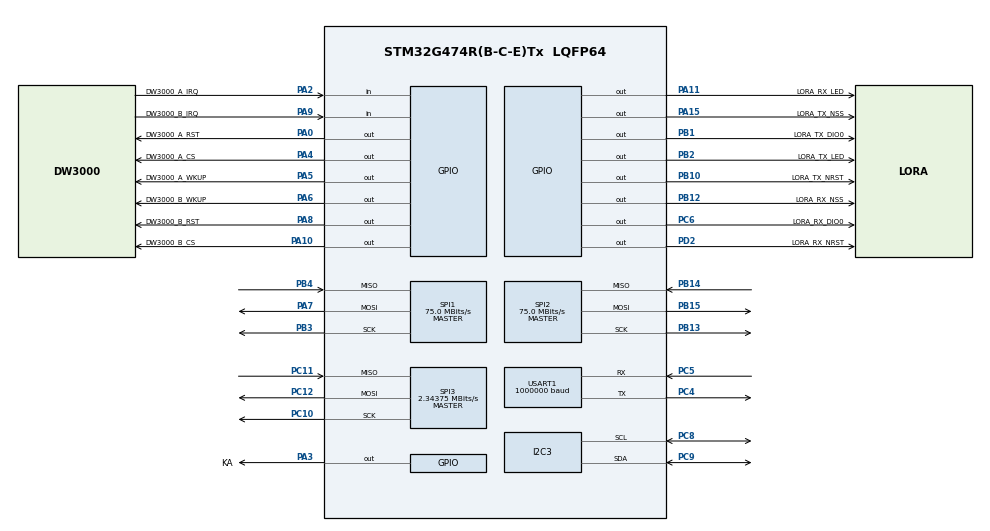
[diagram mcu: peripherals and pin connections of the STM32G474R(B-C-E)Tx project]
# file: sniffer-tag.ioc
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Mcu.Family=STM32G4
Mcu.Name=STM32G474R(B-C-E)Tx
Mcu.Package=LQFP64
NVIC.PriorityGroup=NVIC_PRIORITYGROUP_4
PA0.GPIO_Label=DW3000_A_RST
PA0.Signal=GPIO_Output
PA10.GPIO_Label=DW3000_B_CS
PA10.Signal=GPIO_Output
PA11.GPIO_Label=LORA_RX_LED
PA11.Signal=GPIO_Output
PA13.Signal=SYS_JTMS-SWDIO
PA14.Signal=SYS_JTCK-SWCLK
PA15.GPIO_Label=LORA_TX_NSS
PA15.Signal=GPIO_Output
PA2.GPIO_Label=DW3000_A_IRQ
PA2.Signal=GPIO_Input
PA3.GPIO_Label=KA
PA3.Signal=GPIO_Output
PA4.GPIO_Label=DW3000_A_CS
PA4.Signal=GPIO_Output
PA5.GPIO_Label=DW3000_A_WKUP
PA5.Signal=GPIO_Output
PA6.GPIO_Label=DW3000_B_WKUP
PA6.Signal=GPIO_Output
PA7.Mode=Full_Duplex_Master
PA7.Signal=SPI1_MOSI
PA8.GPIO_Label=DW3000_B_RST
PA8.Signal=GPIO_Output
PA9.GPIO_Label=DW3000_B_IRQ
PA9.Signal=GPIO_Input
PB1.GPIO_Label=LORA_TX_DIO0
PB1.Signal=GPIO_Output
PB10.GPIO_Label=LORA_TX_NRST
PB10.Signal=GPIO_Output
PB12.GPIO_Label=LORA_RX_NSS
PB12.Signal=GPIO_Output
PB13.Mode=Full_Duplex_Master
PB13.Signal=SPI2_SCK
PB14.Mode=Full_Duplex_Master
PB14.Signal=SPI2_MISO
PB15.Mode=Full_Duplex_Master
PB15.Signal=SPI2_MOSI
PB2.GPIO_Label=LORA_TX_LED
PB2.Signal=GPIO_Output
PB3.Mode=Full_Duplex_Master
PB3.Signal=SPI1_SCK
PB4.Mode=Full_Duplex_Master
PB4.Signal=SPI1_MISO
PC10.Mode=Full_Duplex_Master
PC10.Signal=SPI3_SCK
PC11.Mode=Full_Duplex_Master
PC11.Signal=SPI3_MISO
PC12.Mode=Full_Duplex_Master
PC12.Signal=SPI3_MOSI
PC4.Mode=Asynchronous
PC4.Signal=USART1_TX
PC5.Mode=Asynchronous
PC5.Signal=USART1_RX
PC6.GPIO_Label=LORA_RX_DIO0
PC6.Signal=GPIO_Output
PC8.Mode=I2C
PC8.Signal=I2C3_SCL
PC9.Mode=I2C
PC9.Signal=I2C3_SDA
PD2.GPIO_Label=LORA_RX_NRST
PD2.Signal=GPIO_Output
ProjectManager.HeapSize=0x200
ProjectManager.StackSize=0x400
ProjectManager.TargetToolchain=STM32CubeIDE
RCC.ADC12Freq_Value=150000000
RCC.ADC345Freq_Value=150000000
RCC.AHBFreq_Value=150000000
RCC.APB1Freq_Value=150000000
RCC.APB1TimFreq_Value=150000000
RCC.APB2Freq_Value=150000000
RCC.APB2TimFreq_Value=150000000
RCC.CortexFreq_Value=150000000
RCC.EXTERNAL_CLOCK_VALUE=12288000
RCC.HCLKFreq_Value=150000000
RCC.HSE_VALUE=8000000
RCC.HSI48_VALUE=48000000
RCC.HSI_VALUE=16000000
RCC.LSE_VALUE=32768
RCC.PLLM=RCC_PLLM_DIV4
RCC.PLLN=75
RCC.SYSCLKFreq_VALUE=150000000
RCC.SYSCLKSource=RCC_SYSCLKSOURCE_PLLCLK
RCC.USBFreq_Value=150000000
RCC.VCOOutputFreq_Value=300000000
SPI1.CalculateBaudRate=75.0 MBits/s
SPI1.Direction=SPI_DIRECTION_2LINES
SPI1.Mode=SPI_MODE_MASTER
SPI1.VirtualType=VM_MASTER
SPI2.CalculateBaudRate=75.0 MBits/s
SPI2.Direction=SPI_DIRECTION_2LINES
SPI2.Mode=SPI_MODE_MASTER
SPI2.VirtualType=VM_MASTER
SPI3.BaudRatePrescaler=SPI_BAUDRATEPRESCALER_64
SPI3.CalculateBaudRate=2.34375 MBits/s
SPI3.DataSize=SPI_DATASIZE_8BIT
SPI3.Direction=SPI_DIRECTION_2LINES
SPI3.Mode=SPI_MODE_MASTER
SPI3.NSSPMode=SPI_NSS_PULSE_DISABLE
SPI3.VirtualType=VM_MASTER
USART1.BaudRate=1000000
USART1.VirtualMode-Asynchronous=VM_ASYNC
VP_SYS_VS_DBSignals.Mode=DisableDeadBatterySignals
board=custom

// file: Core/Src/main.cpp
/* USER CODE BEGIN Header */
/**
 ******************************************************************************
 * @file           : main.c
 * @brief          : Main program body
 ******************************************************************************
 * @attention
 *
 * Copyright (c) 2024 STMicroelectronics.
 * All rights reserved.
 *
 * This software is licensed under terms that can be found in the LICENSE file
 * in the root directory of this software component.
 * If no LICENSE file comes with this software, it is provided AS-IS.
 *
 ******************************************************************************
 */
/* USER CODE END Header */
#include <sniffer_tag.hpp>
#include "SX1278.h"
#include "main.h"

I2C_HandleTypeDef hi2c3;

SPI_HandleTypeDef hspi1;
SPI_HandleTypeDef hspi2;
SPI_HandleTypeDef hspi3;

UART_HandleTypeDef huart1;

/* USER CODE BEGIN PV */
double *distance_ptr;
TAG_t *tag;
int size = 0;
uint8_t running_device = DEV_UWB3000F27;
Uwb_HW_t uwb_hw_a;
Uwb_HW_t uwb_hw_b;
Uwb_HW_t *hw;
dwt_local_data_t *pdw3000local;
uint8_t crcTable[256];
uint8_t recvChar;
LORA_t lora;
SX1276_HW_t sx1276_hw_tx;
SX1276_HW_t sx1276_hw_rx;
/* USER CODE END PV */

void SystemClock_Config(void);
static void MX_GPIO_Init(void);
static void MX_USART1_UART_Init(void);
static void MX_I2C3_Init(void);
static void MX_SPI1_Init(void);
static void MX_SPI2_Init(void);
static void MX_SPI3_Init(void);

int main(void) {

	/* MCU Configuration--------------------------------------------------------*/

	/* Reset of all peripherals, Initializes the Flash interface and the Systick. */
	HAL_Init();

	/* Configure the system clock */
	SystemClock_Config();

	/* Initialize all configured peripherals */
	MX_GPIO_Init();
	MX_USART1_UART_Init();
	MX_I2C3_Init();
	MX_SPI1_Init();
	MX_SPI2_Init();
	MX_SPI3_Init();
	/* USER CODE BEGIN 2 */
	pdw3000local = new dwt_local_data_t;

	init_sx1276_hw(&sx1276_hw_tx, &hspi1, LORA_TX_NSS_GPIO_Port,
	LORA_TX_NSS_Pin,
	LORA_TX_NRST_GPIO_Port, LORA_TX_NRST_Pin,
	LORA_TX_DIO0_GPIO_Port,
	LORA_TX_DIO0_Pin);

	init_sx1276_hw(&sx1276_hw_rx, &hspi2, LORA_RX_NSS_GPIO_Port,
	LORA_RX_NSS_Pin,
	LORA_RX_NRST_GPIO_Port, LORA_RX_NRST_Pin,
	LORA_RX_DIO0_GPIO_Port,
	LORA_RX_DIO0_Pin);

	HAL_GPIO_WritePin(LORA_TX_LED_GPIO_Port, LORA_TX_LED_Pin, GPIO_PIN_SET);
	HAL_GPIO_WritePin(LORA_RX_LED_GPIO_Port, LORA_RX_LED_Pin, GPIO_PIN_SET);

	lora_init(&lora, &sx1276_hw_tx, &sx1276_hw_rx);

	TAG_List list = { NULL, 0 };

	HAL_GPIO_WritePin(DW3000_B_WKUP_GPIO_Port, DW3000_B_WKUP_Pin, GPIO_PIN_RESET);
	HAL_GPIO_WritePin(DW3000_A_WKUP_GPIO_Port, DW3000_A_WKUP_Pin, GPIO_PIN_RESET);
	HAL_GPIO_WritePin(DW3000_A_CS_GPIO_Port, DW3000_A_CS_Pin, GPIO_PIN_RESET);
	HAL_GPIO_WritePin(DW3000_B_CS_GPIO_Port, DW3000_B_CS_Pin, GPIO_PIN_RESET);

	init_uwb_device(&uwb_hw_a, &hspi3, DW3000_A_CS_GPIO_Port,
	DW3000_A_CS_Pin,
	DW3000_A_RST_GPIO_Port, DW3000_A_RST_Pin);

	init_uwb_device(&uwb_hw_b, &hspi3, DW3000_B_CS_GPIO_Port, DW3000_B_CS_Pin,
			DW3000_B_RST_GPIO_Port, DW3000_B_RST_Pin);

	TAG_t tag;
	reset_TAG_values(&tag);

	TAG_STATUS_t tag_status = TAG_DISCOVERY;
	uint32_t lora_send_timeout = 5000;
	uint32_t lora_send_ticks = HAL_GetTick();
	uint32_t query_timeout = 1000;
	uint32_t query_ticks;

	RDSS_status_t rdss_status;

	/* USER CODE END 2 */

	/* Infinite loop */
	while (1) {
		if (tag_status == TAG_DISCOVERY) {

			if (hw == &uwb_hw_a) {
				hw = &uwb_hw_b;
				tag.distance = &(tag.distance_b);
			} else {
				hw = &uwb_hw_a;
				tag.distance = &(tag.distance_a);
			}

			tag_status = tag_discovery(&tag);

			if (tag_status != TAG_SEND_TIMESTAMP_QUERY)
				tag_status = TAG_DISCOVERY;
			else
				query_ticks = HAL_GetTick();
			set_battery_voltage(&(tag.battery_voltage));
			set_temperature(&(tag.temperature));
			debug(tag, tag_status);

		} else if (tag_status == TAG_SEND_TIMESTAMP_QUERY) {
			if (tag.readings < DISTANCE_READINGS) {
				if (hw == &uwb_hw_a) {
					hw = &uwb_hw_b;
					tag.distance = &(tag.distance_b);
				} else {
					hw = &uwb_hw_a;
					tag.distance = &(tag.distance_a);
				}
				tag.command = TAG_TIMESTAMP_QUERY;
			}
			if (tag.readings == DISTANCE_READINGS - 2) {
				tag.command = TAG_SET_SLEEP_MODE;
				tag_status = TAG_SEND_SET_SLEEP;
			}
			debug(tag, tag_status);
			tag_status = tag_send_timestamp_query(&tag);

			if (tag_status == TAG_SEND_TIMESTAMP_QUERY) {
				tag.readings++;
				tag_status = TAG_SEND_TIMESTAMP_QUERY;

			} else if (tag_status == TAG_END_READINGS) {
				double distance_a_sum = 0;
				double distance_b_sum = 0;
				for (uint8_t i = 0; i < tag.distance_a.counter; i++)
					distance_a_sum += tag.distance_a.readings[i];

				for (uint8_t i = 0; i < tag.distance_b.counter; i++)
					distance_b_sum += tag.distance_b.readings[i];

				tag.distance_a.value = (uint16_t) ((distance_a_sum * 100)
						/ tag.distance_a.counter);
				tag.distance_b.value = (uint16_t) ((distance_b_sum * 100)
						/ tag.distance_b.counter);
				insert_tag(&list, tag);
				tag_status = TAG_DISCOVERY;
				reset_TAG_values(&tag);
			} else {
				tag_status = TAG_SEND_TIMESTAMP_QUERY;
			}
			debug(tag, tag_status);
			if (HAL_GetTick() - query_ticks > query_timeout) {
				tag_status = TAG_DISCOVERY;
				reset_TAG_values(&tag);
			}

		}

		if (read_lora_packet(&lora) > 0) {
			rdss_status = rdss_validation(lora.rxData, lora.rxSize, 0x00);
			if (rdss_status == DATA_OK) {
				uint8_t *rx = lora.rxData;
				size_t temp_value = 1 + list.count * SERIALIZED_TAG_SIZE; // Or use uint32_t
				uint8_t tag_bytes = (uint8_t) temp_value;
				uint8_t response_length = calculate_frame_length(tag_bytes);
				uint8_t tx[response_length];
				memset(tx, 0, response_length);
				memcpy(tx, rx, LORA_DATA_LENGHT_INDEX_1);
				memcpy(tx + LORA_DATA_LENGHT_INDEX_1, &tag_bytes,
						sizeof(tag_bytes));
				uint8_t *tx_data = tx + LORA_DATA_START_INDEX;
				tx_data[0] = list.count;
				tx_data++;
				serialize_tag_list(&list, tx_data);
				uint8_t CRC_INDEX = LORA_DATA_START_INDEX
						+ tx[LORA_DATA_LENGHT_INDEX_1];
				uint8_t END_INDEX = CRC_INDEX + CRC_SIZE;
				setCrc(tx, CRC_INDEX);
				tx[END_INDEX] = LTEL_END_MARK;
				HAL_GPIO_WritePin(LORA_TX_LED_GPIO_Port, LORA_TX_LED_Pin,
						GPIO_PIN_RESET);
				write_lora_RegFifo(lora.txhw, tx, response_length);
				start_lora_transmission(lora.txhw);
				HAL_GPIO_WritePin(LORA_TX_LED_GPIO_Port, LORA_TX_LED_Pin,
						GPIO_PIN_SET);
				serialize_tag_list(&list, tx_data);
				free(tx);
				print_all_tags(&list, tag_status);
				print_serialized_tags(&list);
				free_tag_list(&list);
				restart_lora_rx_continuous_mode(&lora);
			} else {
				lora_reset(lora.txhw);
				lora_reset(lora.rxhw);
				init_lora_parameters(&lora);
			}
		}

		if (((HAL_GetTick() - lora_send_ticks) > lora_send_timeout)
				&& tag_status == TAG_DISCOVERY) {
			debug_status(tag_status);
			size_t temp_value = 1 + list.count * SERIALIZED_TAG_SIZE; // Or use uint32_t
			uint8_t tag_bytes = (uint8_t) temp_value;
			uint8_t response_length = calculate_frame_length(tag_bytes);
			uint8_t tx[response_length];
			memset(tx, 0, response_length);
			memcpy(tx + LORA_DATA_LENGHT_INDEX_1, &tag_bytes,
					sizeof(tag_bytes));
			uint8_t *tx_data = tx + LORA_DATA_START_INDEX;
			tx_data[0] = list.count;
			tx_data++;
			serialize_tag_list(&list, tx_data);
			uint8_t CRC_INDEX = LORA_DATA_START_INDEX
					+ tx[LORA_DATA_LENGHT_INDEX_1];
			uint8_t END_INDEX = CRC_INDEX + CRC_SIZE;
			setCrc(tx, CRC_INDEX);
			tx[END_INDEX] = LTEL_END_MARK;
			print_all_tags(&list, tag_status);
			print_serialized_tags(&list);
			print_tx_hex(tx, response_length);
			free_tag_list(&list);
			lora_send_ticks = HAL_GetTick();
		}

	}
}

void SystemClock_Config(void) {
	RCC_OscInitTypeDef RCC_OscInitStruct = { 0 };
	RCC_ClkInitTypeDef RCC_ClkInitStruct = { 0 };

	/** Configure the main internal regulator output voltage
	 */
	HAL_PWREx_ControlVoltageScaling(PWR_REGULATOR_VOLTAGE_SCALE1);

	/** Initializes the RCC Oscillators according to the specified parameters
	 * in the RCC_OscInitTypeDef structure.
	 */
	RCC_OscInitStruct.OscillatorType = RCC_OSCILLATORTYPE_HSI;
	RCC_OscInitStruct.HSIState = RCC_HSI_ON;
	RCC_OscInitStruct.HSICalibrationValue = RCC_HSICALIBRATION_DEFAULT;
	RCC_OscInitStruct.PLL.PLLState = RCC_PLL_NONE;
	if (HAL_RCC_OscConfig(&RCC_OscInitStruct) != HAL_OK) {
		Error_Handler();
	}

	/** Initializes the CPU, AHB and APB buses clocks
	 */
	RCC_ClkInitStruct.ClockType = RCC_CLOCKTYPE_HCLK | RCC_CLOCKTYPE_SYSCLK
			| RCC_CLOCKTYPE_PCLK1 | RCC_CLOCKTYPE_PCLK2;
	RCC_ClkInitStruct.SYSCLKSource = RCC_SYSCLKSOURCE_HSI;
	RCC_ClkInitStruct.AHBCLKDivider = RCC_SYSCLK_DIV1;
	RCC_ClkInitStruct.APB1CLKDivider = RCC_HCLK_DIV1;
	RCC_ClkInitStruct.APB2CLKDivider = RCC_HCLK_DIV1;

	if (HAL_RCC_ClockConfig(&RCC_ClkInitStruct, FLASH_LATENCY_0) != HAL_OK) {
		Error_Handler();
	}
}

static void MX_I2C3_Init(void) {

	hi2c3.Instance = I2C3;
	hi2c3.Init.Timing = 0x00303D5B;
	hi2c3.Init.OwnAddress1 = 0;
	hi2c3.Init.AddressingMode = I2C_ADDRESSINGMODE_7BIT;
	hi2c3.Init.DualAddressMode = I2C_DUALADDRESS_DISABLE;
	hi2c3.Init.OwnAddress2 = 0;
	hi2c3.Init.OwnAddress2Masks = I2C_OA2_NOMASK;
	hi2c3.Init.GeneralCallMode = I2C_GENERALCALL_DISABLE;
	hi2c3.Init.NoStretchMode = I2C_NOSTRETCH_DISABLE;
	if (HAL_I2C_Init(&hi2c3) != HAL_OK) {
		Error_Handler();
	}

	/** Configure Analogue filter
	 */
	if (HAL_I2CEx_ConfigAnalogFilter(&hi2c3, I2C_ANALOGFILTER_ENABLE)
			!= HAL_OK) {
		Error_Handler();
	}

	/** Configure Digital filter
	 */
	if (HAL_I2CEx_ConfigDigitalFilter(&hi2c3, 0) != HAL_OK) {
		Error_Handler();
	}

}

static void MX_SPI1_Init(void) {

	/* SPI1 parameter configuration*/
	hspi1.Instance = SPI1;
	hspi1.Init.Mode = SPI_MODE_MASTER;
	hspi1.Init.Direction = SPI_DIRECTION_2LINES;
	hspi1.Init.DataSize = SPI_DATASIZE_4BIT;
	hspi1.Init.CLKPolarity = SPI_POLARITY_LOW;
	hspi1.Init.CLKPhase = SPI_PHASE_1EDGE;
	hspi1.Init.NSS = SPI_NSS_SOFT;
	hspi1.Init.BaudRatePrescaler = SPI_BAUDRATEPRESCALER_2;
	hspi1.Init.FirstBit = SPI_FIRSTBIT_MSB;
	hspi1.Init.TIMode = SPI_TIMODE_DISABLE;
	hspi1.Init.CRCCalculation = SPI_CRCCALCULATION_DISABLE;
	hspi1.Init.CRCPolynomial = 7;
	hspi1.Init.CRCLength = SPI_CRC_LENGTH_DATASIZE;
	hspi1.Init.NSSPMode = SPI_NSS_PULSE_ENABLE;
	if (HAL_SPI_Init(&hspi1) != HAL_OK) {
		Error_Handler();
	}

}

static void MX_SPI2_Init(void) {

	/* SPI2 parameter configuration*/
	hspi2.Instance = SPI2;
	hspi2.Init.Mode = SPI_MODE_MASTER;
	hspi2.Init.Direction = SPI_DIRECTION_2LINES;
	hspi2.Init.DataSize = SPI_DATASIZE_4BIT;
	hspi2.Init.CLKPolarity = SPI_POLARITY_LOW;
	hspi2.Init.CLKPhase = SPI_PHASE_1EDGE;
	hspi2.Init.NSS = SPI_NSS_SOFT;
	hspi2.Init.BaudRatePrescaler = SPI_BAUDRATEPRESCALER_2;
	hspi2.Init.FirstBit = SPI_FIRSTBIT_MSB;
	hspi2.Init.TIMode = SPI_TIMODE_DISABLE;
	hspi2.Init.CRCCalculation = SPI_CRCCALCULATION_DISABLE;
	hspi2.Init.CRCPolynomial = 7;
	hspi2.Init.CRCLength = SPI_CRC_LENGTH_DATASIZE;
	hspi2.Init.NSSPMode = SPI_NSS_PULSE_ENABLE;
	if (HAL_SPI_Init(&hspi2) != HAL_OK) {
		Error_Handler();
	}

}

static void MX_SPI3_Init(void)
{

  /* SPI3 parameter configuration*/
  hspi3.Instance = SPI3;
  hspi3.Init.Mode = SPI_MODE_MASTER;
  hspi3.Init.Direction = SPI_DIRECTION_2LINES;
  hspi3.Init.DataSize = SPI_DATASIZE_8BIT;
  hspi3.Init.CLKPolarity = SPI_POLARITY_LOW;
  hspi3.Init.CLKPhase = SPI_PHASE_1EDGE;
  hspi3.Init.NSS = SPI_NSS_SOFT;
  hspi3.Init.BaudRatePrescaler = SPI_BAUDRATEPRESCALER_64;
  hspi3.Init.FirstBit = SPI_FIRSTBIT_MSB;
  hspi3.Init.TIMode = SPI_TIMODE_DISABLE;
  hspi3.Init.CRCCalculation = SPI_CRCCALCULATION_DISABLE;
  hspi3.Init.CRCPolynomial = 7;
  hspi3.Init.CRCLength = SPI_CRC_LENGTH_DATASIZE;
  hspi3.Init.NSSPMode = SPI_NSS_PULSE_DISABLE;
  if (HAL_SPI_Init(&hspi3) != HAL_OK)
  {
    Error_Handler();
  }

}

static void MX_USART1_UART_Init(void) {

	huart1.Instance = USART1;
	huart1.Init.BaudRate = 1000000;
	huart1.Init.WordLength = UART_WORDLENGTH_8B;
	huart1.Init.StopBits = UART_STOPBITS_1;
	huart1.Init.Parity = UART_PARITY_NONE;
	huart1.Init.Mode = UART_MODE_TX_RX;
	huart1.Init.HwFlowCtl = UART_HWCONTROL_NONE;
	huart1.Init.OverSampling = UART_OVERSAMPLING_16;
	huart1.Init.OneBitSampling = UART_ONE_BIT_SAMPLE_DISABLE;
	huart1.Init.ClockPrescaler = UART_PRESCALER_DIV1;
	huart1.AdvancedInit.AdvFeatureInit = UART_ADVFEATURE_NO_INIT;
	if (HAL_UART_Init(&huart1) != HAL_OK) {
		Error_Handler();
	}
	if (HAL_UARTEx_SetTxFifoThreshold(&huart1, UART_TXFIFO_THRESHOLD_1_8)
			!= HAL_OK) {
		Error_Handler();
	}
	if (HAL_UARTEx_SetRxFifoThreshold(&huart1, UART_RXFIFO_THRESHOLD_1_8)
			!= HAL_OK) {
		Error_Handler();
	}
	if (HAL_UARTEx_DisableFifoMode(&huart1) != HAL_OK) {
		Error_Handler();
	}

}

static void MX_GPIO_Init(void) {
	GPIO_InitTypeDef GPIO_InitStruct = { 0 };

	/* GPIO Ports Clock Enable */
	__HAL_RCC_GPIOA_CLK_ENABLE();
	__HAL_RCC_GPIOC_CLK_ENABLE();
	__HAL_RCC_GPIOB_CLK_ENABLE();
	__HAL_RCC_GPIOD_CLK_ENABLE();

	/*Configure GPIO pin Output Level */
	HAL_GPIO_WritePin(GPIOA,
			DW3000_A_RST_Pin | KA_Pin | DW3000_A_CS_Pin | DW3000_A_WKUP_Pin
					| DW3000_B_WKUP_Pin | DW3000_B_RST_Pin | DW3000_B_CS_Pin
					| LORA_RX_LED_Pin | LORA_TX_NSS_Pin, GPIO_PIN_RESET);

	/*Configure GPIO pin Output Level */
	HAL_GPIO_WritePin(GPIOB,
	LORA_TX_DIO0_Pin | LORA_TX_LED_Pin | LORA_TX_NRST_Pin | LORA_RX_NSS_Pin,
			GPIO_PIN_RESET);

	/*Configure GPIO pin Output Level */
	HAL_GPIO_WritePin(LORA_RX_DIO0_GPIO_Port, LORA_RX_DIO0_Pin, GPIO_PIN_RESET);

	/*Configure GPIO pin Output Level */
	HAL_GPIO_WritePin(LORA_RX_NRST_GPIO_Port, LORA_RX_NRST_Pin, GPIO_PIN_RESET);

	/*Configure GPIO pins : DW3000_A_RST_Pin KA_Pin DW3000_A_CS_Pin DW3000_A_WKUP_Pin
	 DW3000_B_WKUP_Pin DW3000_B_RST_Pin DW3000_B_CS_Pin LORA_RX_LED_Pin
	 LORA_TX_NSS_Pin */
	GPIO_InitStruct.Pin = DW3000_A_RST_Pin | KA_Pin | DW3000_A_CS_Pin
			| DW3000_A_WKUP_Pin | DW3000_B_WKUP_Pin | DW3000_B_RST_Pin
			| DW3000_B_CS_Pin | LORA_RX_LED_Pin | LORA_TX_NSS_Pin;
	GPIO_InitStruct.Mode = GPIO_MODE_OUTPUT_PP;
	GPIO_InitStruct.Pull = GPIO_NOPULL;
	GPIO_InitStruct.Speed = GPIO_SPEED_FREQ_LOW;
	HAL_GPIO_Init(GPIOA, &GPIO_InitStruct);

	/*Configure GPIO pins : DW3000_A_IRQ_Pin DW3000_B_IRQ_Pin */
	GPIO_InitStruct.Pin = DW3000_A_IRQ_Pin | DW3000_B_IRQ_Pin;
	GPIO_InitStruct.Mode = GPIO_MODE_INPUT;
	GPIO_InitStruct.Pull = GPIO_NOPULL;
	HAL_GPIO_Init(GPIOA, &GPIO_InitStruct);

	/*Configure GPIO pins : LORA_TX_DIO0_Pin LORA_TX_LED_Pin LORA_TX_NRST_Pin LORA_RX_NSS_Pin */
	GPIO_InitStruct.Pin = LORA_TX_DIO0_Pin | LORA_TX_LED_Pin | LORA_TX_NRST_Pin
			| LORA_RX_NSS_Pin;
	GPIO_InitStruct.Mode = GPIO_MODE_OUTPUT_PP;
	GPIO_InitStruct.Pull = GPIO_NOPULL;
	GPIO_InitStruct.Speed = GPIO_SPEED_FREQ_LOW;
	HAL_GPIO_Init(GPIOB, &GPIO_InitStruct);

	/*Configure GPIO pin : LORA_RX_DIO0_Pin */
	GPIO_InitStruct.Pin = LORA_RX_DIO0_Pin;
	GPIO_InitStruct.Mode = GPIO_MODE_OUTPUT_PP;
	GPIO_InitStruct.Pull = GPIO_NOPULL;
	GPIO_InitStruct.Speed = GPIO_SPEED_FREQ_LOW;
	HAL_GPIO_Init(LORA_RX_DIO0_GPIO_Port, &GPIO_InitStruct);

	/*Configure GPIO pin : LORA_RX_NRST_Pin */
	GPIO_InitStruct.Pin = LORA_RX_NRST_Pin;
	GPIO_InitStruct.Mode = GPIO_MODE_OUTPUT_PP;
	GPIO_InitStruct.Pull = GPIO_NOPULL;
	GPIO_InitStruct.Speed = GPIO_SPEED_FREQ_LOW;
	HAL_GPIO_Init(LORA_RX_NRST_GPIO_Port, &GPIO_InitStruct);

}

int keepAliveStartTicks = 0;
void Error_Handler(void) {
	/* USER CODE BEGIN Error_Handler_Debug */
	/* User can add his own implementation to report the HAL error return state */
	__disable_irq();

	while (1) {
		if (keepAliveStartTicks > 50000) {
			keepAliveStartTicks = 0;
			HAL_GPIO_WritePin(KA_GPIO_Port, KA_Pin, GPIO_PIN_SET);
		} else if (keepAliveStartTicks > 25000)
			HAL_GPIO_WritePin(KA_GPIO_Port, KA_Pin, GPIO_PIN_RESET);
		keepAliveStartTicks++;
	}
	/* USER CODE END Error_Handler_Debug */
}
